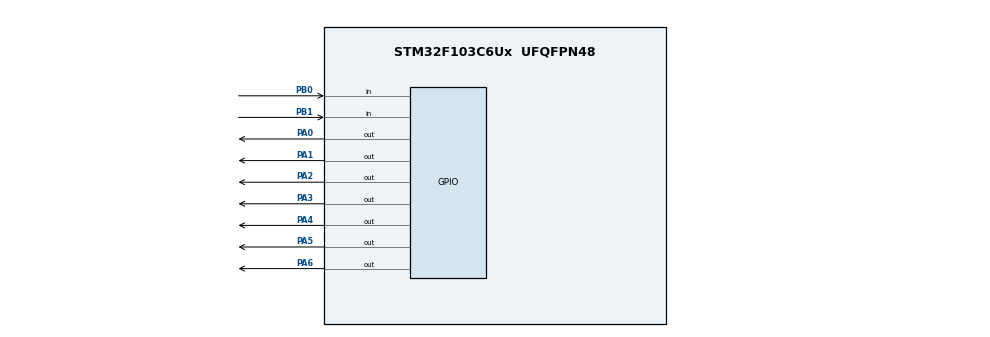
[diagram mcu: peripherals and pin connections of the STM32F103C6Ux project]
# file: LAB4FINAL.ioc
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Mcu.Family=STM32F1
Mcu.Name=STM32F103C6Ux
Mcu.Package=UFQFPN48
NVIC.PriorityGroup=NVIC_PRIORITYGROUP_4
NVIC.TIM2_IRQn=true\:0\:0\:false\:false\:true\:true\:true
PA0-WKUP.Signal=GPIO_Output
PA1.Signal=GPIO_Output
PA10.Signal=USART1_RX
PA2.Signal=GPIO_Output
PA3.Signal=GPIO_Output
PA4.Signal=GPIO_Output
PA5.Signal=GPIO_Output
PA6.Signal=GPIO_Output
PA9.Signal=USART1_TX
PB0.GPIO_PuPd=GPIO_PULLUP
PB0.Signal=GPIO_Input
PB1.GPIO_PuPd=GPIO_PULLUP
PB1.Signal=GPIO_Input
ProjectManager.HeapSize=0x200
ProjectManager.StackSize=0x400
ProjectManager.TargetToolchain=STM32CubeIDE
RCC.APB1Freq_Value=8000000
RCC.APB2Freq_Value=8000000
VP_SYS_VS_ND.Mode=No_Debug
VP_TIM2_VS_ClockSourceINT.Mode=Internal
board=custom

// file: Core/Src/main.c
/* USER CODE BEGIN Header */
/**
  ******************************************************************************
  * @file           : main.c
  * @brief          : Main program body
  ******************************************************************************
  * @attention
  *
  * <h2><center>&copy; Copyright (c) 2026 STMicroelectronics.
  * All rights reserved.</center></h2>
  *
  * This software component is licensed by ST under BSD 3-Clause license,
  * the "License"; You may not use this file except in compliance with
  * the License.
  *
  ******************************************************************************
  */
/* USER CODE END Header */

#include "main.h"

/* USER CODE BEGIN Includes */
#include "scheduler.h"
#include <stdio.h>
/* USER CODE END Includes */

TIM_HandleTypeDef htim2;

void SystemClock_Config(void);
static void MX_GPIO_Init(void);
static void MX_TIM2_Init(void);

/* USER CODE BEGIN 0 */

void Task_500ms(void)
{
    HAL_GPIO_TogglePin(GPIOA, GPIO_PIN_1);
}

void Task_1000ms(void)
{
    HAL_GPIO_TogglePin(GPIOA, GPIO_PIN_2);
}

void Task_1500ms(void)
{
    HAL_GPIO_TogglePin(GPIOA, GPIO_PIN_3);
}

void Task_2000ms(void)
{
    HAL_GPIO_TogglePin(GPIOA, GPIO_PIN_4);
}

void Task_2500ms(void)
{
    HAL_GPIO_TogglePin(GPIOA, GPIO_PIN_5);
}

void HAL_TIM_PeriodElapsedCallback(TIM_HandleTypeDef *htim)
{
    if (htim->Instance == TIM2)
    {
        SCH_Update();
    }
}

/* USER CODE END 0 */

int main(void)
{

  HAL_Init();

  SystemClock_Config();

  MX_GPIO_Init();
  MX_TIM2_Init();

  /* USER CODE BEGIN 2 */
  SCH_Init();

  HAL_TIM_Base_Start_IT(&htim2);

  SCH_Add_Task(Task_500ms, 50, 50);
  SCH_Add_Task(Task_1000ms, 100, 100);
  SCH_Add_Task(Task_1500ms, 150, 150);
  SCH_Add_Task(Task_2000ms, 200, 200);
  SCH_Add_Task(Task_2500ms, 250, 250);

  /* USER CODE END 2 */

  while (1)
  {
    /* USER CODE BEGIN WHILE */

    SCH_Dispatch_Tasks();
    HAL_Delay(1);

    /* USER CODE END WHILE */

  }
}

void SystemClock_Config(void)
{
  RCC_OscInitTypeDef RCC_OscInitStruct = {0};
  RCC_ClkInitTypeDef RCC_ClkInitStruct = {0};

  RCC_OscInitStruct.OscillatorType = RCC_OSCILLATORTYPE_HSI;
  RCC_OscInitStruct.HSIState = RCC_HSI_ON;
  RCC_OscInitStruct.HSICalibrationValue = RCC_HSICALIBRATION_DEFAULT;
  RCC_OscInitStruct.PLL.PLLState = RCC_PLL_NONE;

  if (HAL_RCC_OscConfig(&RCC_OscInitStruct) != HAL_OK)
  {
    Error_Handler();
  }

  RCC_ClkInitStruct.ClockType = RCC_CLOCKTYPE_HCLK |
                                RCC_CLOCKTYPE_SYSCLK |
                                RCC_CLOCKTYPE_PCLK1 |
                                RCC_CLOCKTYPE_PCLK2;

  RCC_ClkInitStruct.SYSCLKSource = RCC_SYSCLKSOURCE_HSI;
  RCC_ClkInitStruct.AHBCLKDivider = RCC_SYSCLK_DIV1;
  RCC_ClkInitStruct.APB1CLKDivider = RCC_HCLK_DIV1;
  RCC_ClkInitStruct.APB2CLKDivider = RCC_HCLK_DIV1;

  if (HAL_RCC_ClockConfig(&RCC_ClkInitStruct,
                          FLASH_LATENCY_0) != HAL_OK)
  {
    Error_Handler();
  }
}

static void MX_TIM2_Init(void)
{
  TIM_ClockConfigTypeDef sClockSourceConfig = {0};
  TIM_MasterConfigTypeDef sMasterConfig = {0};

  htim2.Instance = TIM2;
  htim2.Init.Prescaler = 79;
  htim2.Init.CounterMode = TIM_COUNTERMODE_UP;
  htim2.Init.Period = 999;
  htim2.Init.ClockDivision = TIM_CLOCKDIVISION_DIV1;
  htim2.Init.AutoReloadPreload = TIM_AUTORELOAD_PRELOAD_DISABLE;

  if (HAL_TIM_Base_Init(&htim2) != HAL_OK)
  {
    Error_Handler();
  }

  sClockSourceConfig.ClockSource = TIM_CLOCKSOURCE_INTERNAL;

  if (HAL_TIM_ConfigClockSource(&htim2,
                                &sClockSourceConfig) != HAL_OK)
  {
    Error_Handler();
  }

  sMasterConfig.MasterOutputTrigger = TIM_TRGO_RESET;
  sMasterConfig.MasterSlaveMode = TIM_MASTERSLAVEMODE_DISABLE;

  if (HAL_TIMEx_MasterConfigSynchronization(&htim2,
                                            &sMasterConfig) != HAL_OK)
  {
    Error_Handler();
  }
}

/**
  * @brief UART MSP Initialization
  */

static void MX_GPIO_Init(void)
{
  GPIO_InitTypeDef GPIO_InitStruct = {0};

  __HAL_RCC_GPIOA_CLK_ENABLE();
  __HAL_RCC_GPIOB_CLK_ENABLE();

  HAL_GPIO_WritePin(GPIOA,
                    GPIO_PIN_1 | GPIO_PIN_2 |
                    GPIO_PIN_3 | GPIO_PIN_4 |
                    GPIO_PIN_5 | GPIO_PIN_6 |
                    GPIO_PIN_7,
                    GPIO_PIN_RESET);

  GPIO_InitStruct.Pin = GPIO_PIN_1 | GPIO_PIN_2 |
                        GPIO_PIN_3 | GPIO_PIN_4 |
                        GPIO_PIN_5 | GPIO_PIN_6 |
                        GPIO_PIN_7;

  GPIO_InitStruct.Mode = GPIO_MODE_OUTPUT_PP;
  GPIO_InitStruct.Pull = GPIO_NOPULL;
  GPIO_InitStruct.Speed = GPIO_SPEED_FREQ_LOW;

  HAL_GPIO_Init(GPIOA, &GPIO_InitStruct);

  GPIO_InitStruct.Pin = GPIO_PIN_0 |
                        GPIO_PIN_1 |
                        GPIO_PIN_2;

  GPIO_InitStruct.Mode = GPIO_MODE_INPUT;
  GPIO_InitStruct.Pull = GPIO_PULLUP;

  HAL_GPIO_Init(GPIOB, &GPIO_InitStruct);
}

void Error_Handler(void)
{
  __disable_irq();

  while (1)
  {
  }
}
